# Generated by FakeRAM 2.0
VERSION 5.7 ;
BUSBITCHARS "[]" ;
PROPERTYDEFINITIONS
  MACRO width INTEGER ;
  MACRO depth INTEGER ;
  MACRO banks INTEGER ;
END PROPERTYDEFINITIONS
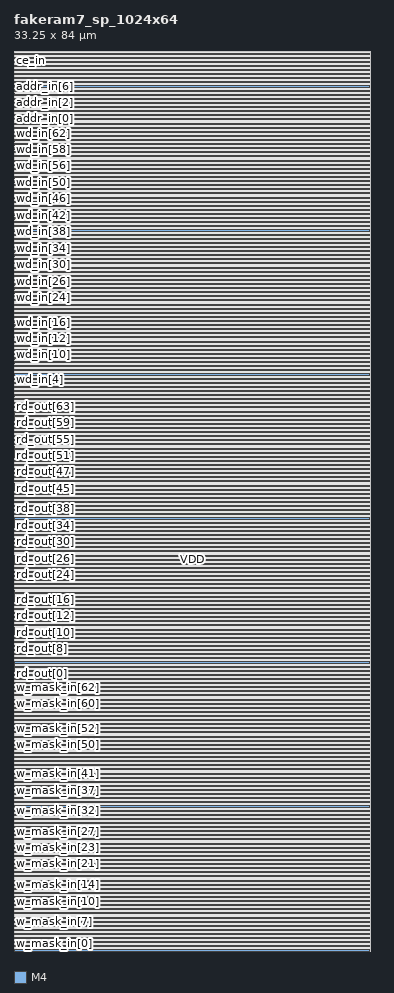
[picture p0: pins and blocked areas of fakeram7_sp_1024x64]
MACRO fakeram7_sp_1024x64
  PROPERTY width 64 ;
  PROPERTY depth 1024 ;
  PROPERTY banks 4 ;
  FOREIGN fakeram7_sp_1024x64 0 0 ;
  SYMMETRY X Y ;
  SIZE 33.250 BY 84.000 ;
  CLASS BLOCK ;
  PIN w_mask_in[0]
    DIRECTION INPUT ;
    USE SIGNAL ;
    SHAPE ABUTMENT ;
    PORT
      LAYER M4 ;
      RECT 0.000 0.048 0.024 0.072 ;
    END
  END w_mask_in[0]
  PIN w_mask_in[1]
    DIRECTION INPUT ;
    USE SIGNAL ;
    SHAPE ABUTMENT ;
    PORT
      LAYER M4 ;
      RECT 0.000 0.432 0.024 0.456 ;
    END
  END w_mask_in[1]
  PIN w_mask_in[2]
    DIRECTION INPUT ;
    USE SIGNAL ;
    SHAPE ABUTMENT ;
    PORT
      LAYER M4 ;
      RECT 0.000 0.816 0.024 0.840 ;
    END
  END w_mask_in[2]
  PIN w_mask_in[3]
    DIRECTION INPUT ;
    USE SIGNAL ;
    SHAPE ABUTMENT ;
    PORT
      LAYER M4 ;
      RECT 0.000 1.200 0.024 1.224 ;
    END
  END w_mask_in[3]
  PIN w_mask_in[4]
    DIRECTION INPUT ;
    USE SIGNAL ;
    SHAPE ABUTMENT ;
    PORT
      LAYER M4 ;
      RECT 0.000 1.584 0.024 1.608 ;
    END
  END w_mask_in[4]
  PIN w_mask_in[5]
    DIRECTION INPUT ;
    USE SIGNAL ;
    SHAPE ABUTMENT ;
    PORT
      LAYER M4 ;
      RECT 0.000 1.968 0.024 1.992 ;
    END
  END w_mask_in[5]
  PIN w_mask_in[6]
    DIRECTION INPUT ;
    USE SIGNAL ;
    SHAPE ABUTMENT ;
    PORT
      LAYER M4 ;
      RECT 0.000 2.352 0.024 2.376 ;
    END
  END w_mask_in[6]
  PIN w_mask_in[7]
    DIRECTION INPUT ;
    USE SIGNAL ;
    SHAPE ABUTMENT ;
    PORT
      LAYER M4 ;
      RECT 0.000 2.736 0.024 2.760 ;
    END
  END w_mask_in[7]
  PIN w_mask_in[8]
    DIRECTION INPUT ;
    USE SIGNAL ;
    SHAPE ABUTMENT ;
    PORT
      LAYER M4 ;
      RECT 0.000 3.120 0.024 3.144 ;
    END
  END w_mask_in[8]
  PIN w_mask_in[9]
    DIRECTION INPUT ;
    USE SIGNAL ;
    SHAPE ABUTMENT ;
    PORT
      LAYER M4 ;
      RECT 0.000 3.504 0.024 3.528 ;
    END
  END w_mask_in[9]
  PIN w_mask_in[10]
    DIRECTION INPUT ;
    USE SIGNAL ;
    SHAPE ABUTMENT ;
    PORT
      LAYER M4 ;
      RECT 0.000 3.888 0.024 3.912 ;
    END
  END w_mask_in[10]
  PIN w_mask_in[11]
    DIRECTION INPUT ;
    USE SIGNAL ;
    SHAPE ABUTMENT ;
    PORT
      LAYER M4 ;
      RECT 0.000 4.272 0.024 4.296 ;
    END
  END w_mask_in[11]
  PIN w_mask_in[12]
    DIRECTION INPUT ;
    USE SIGNAL ;
    SHAPE ABUTMENT ;
    PORT
      LAYER M4 ;
      RECT 0.000 4.656 0.024 4.680 ;
    END
  END w_mask_in[12]
  PIN w_mask_in[13]
    DIRECTION INPUT ;
    USE SIGNAL ;
    SHAPE ABUTMENT ;
    PORT
      LAYER M4 ;
      RECT 0.000 5.040 0.024 5.064 ;
    END
  END w_mask_in[13]
  PIN w_mask_in[14]
    DIRECTION INPUT ;
    USE SIGNAL ;
    SHAPE ABUTMENT ;
    PORT
      LAYER M4 ;
      RECT 0.000 5.424 0.024 5.448 ;
    END
  END w_mask_in[14]
  PIN w_mask_in[15]
    DIRECTION INPUT ;
    USE SIGNAL ;
    SHAPE ABUTMENT ;
    PORT
      LAYER M4 ;
      RECT 0.000 5.808 0.024 5.832 ;
    END
  END w_mask_in[15]
  PIN w_mask_in[16]
    DIRECTION INPUT ;
    USE SIGNAL ;
    SHAPE ABUTMENT ;
    PORT
      LAYER M4 ;
      RECT 0.000 6.192 0.024 6.216 ;
    END
  END w_mask_in[16]
  PIN w_mask_in[17]
    DIRECTION INPUT ;
    USE SIGNAL ;
    SHAPE ABUTMENT ;
    PORT
      LAYER M4 ;
      RECT 0.000 6.576 0.024 6.600 ;
    END
  END w_mask_in[17]
  PIN w_mask_in[18]
    DIRECTION INPUT ;
    USE SIGNAL ;
    SHAPE ABUTMENT ;
    PORT
      LAYER M4 ;
      RECT 0.000 6.960 0.024 6.984 ;
    END
  END w_mask_in[18]
  PIN w_mask_in[19]
    DIRECTION INPUT ;
    USE SIGNAL ;
    SHAPE ABUTMENT ;
    PORT
      LAYER M4 ;
      RECT 0.000 7.344 0.024 7.368 ;
    END
  END w_mask_in[19]
  PIN w_mask_in[20]
    DIRECTION INPUT ;
    USE SIGNAL ;
    SHAPE ABUTMENT ;
    PORT
      LAYER M4 ;
      RECT 0.000 7.728 0.024 7.752 ;
    END
  END w_mask_in[20]
  PIN w_mask_in[21]
    DIRECTION INPUT ;
    USE SIGNAL ;
    SHAPE ABUTMENT ;
    PORT
      LAYER M4 ;
      RECT 0.000 8.112 0.024 8.136 ;
    END
  END w_mask_in[21]
  PIN w_mask_in[22]
    DIRECTION INPUT ;
    USE SIGNAL ;
    SHAPE ABUTMENT ;
    PORT
      LAYER M4 ;
      RECT 0.000 8.496 0.024 8.520 ;
    END
  END w_mask_in[22]
  PIN w_mask_in[23]
    DIRECTION INPUT ;
    USE SIGNAL ;
    SHAPE ABUTMENT ;
    PORT
      LAYER M4 ;
      RECT 0.000 8.880 0.024 8.904 ;
    END
  END w_mask_in[23]
  PIN w_mask_in[24]
    DIRECTION INPUT ;
    USE SIGNAL ;
    SHAPE ABUTMENT ;
    PORT
      LAYER M4 ;
      RECT 0.000 9.264 0.024 9.288 ;
    END
  END w_mask_in[24]
  PIN w_mask_in[25]
    DIRECTION INPUT ;
    USE SIGNAL ;
    SHAPE ABUTMENT ;
    PORT
      LAYER M4 ;
      RECT 0.000 9.648 0.024 9.672 ;
    END
  END w_mask_in[25]
  PIN w_mask_in[26]
    DIRECTION INPUT ;
    USE SIGNAL ;
    SHAPE ABUTMENT ;
    PORT
      LAYER M4 ;
      RECT 0.000 10.032 0.024 10.056 ;
    END
  END w_mask_in[26]
  PIN w_mask_in[27]
    DIRECTION INPUT ;
    USE SIGNAL ;
    SHAPE ABUTMENT ;
    PORT
      LAYER M4 ;
      RECT 0.000 10.416 0.024 10.440 ;
    END
  END w_mask_in[27]
  PIN w_mask_in[28]
    DIRECTION INPUT ;
    USE SIGNAL ;
    SHAPE ABUTMENT ;
    PORT
      LAYER M4 ;
      RECT 0.000 10.800 0.024 10.824 ;
    END
  END w_mask_in[28]
  PIN w_mask_in[29]
    DIRECTION INPUT ;
    USE SIGNAL ;
    SHAPE ABUTMENT ;
    PORT
      LAYER M4 ;
      RECT 0.000 11.184 0.024 11.208 ;
    END
  END w_mask_in[29]
  PIN w_mask_in[30]
    DIRECTION INPUT ;
    USE SIGNAL ;
    SHAPE ABUTMENT ;
    PORT
      LAYER M4 ;
      RECT 0.000 11.568 0.024 11.592 ;
    END
  END w_mask_in[30]
  PIN w_mask_in[31]
    DIRECTION INPUT ;
    USE SIGNAL ;
    SHAPE ABUTMENT ;
    PORT
      LAYER M4 ;
      RECT 0.000 11.952 0.024 11.976 ;
    END
  END w_mask_in[31]
  PIN w_mask_in[32]
    DIRECTION INPUT ;
    USE SIGNAL ;
    SHAPE ABUTMENT ;
    PORT
      LAYER M4 ;
      RECT 0.000 12.336 0.024 12.360 ;
    END
  END w_mask_in[32]
  PIN w_mask_in[33]
    DIRECTION INPUT ;
    USE SIGNAL ;
    SHAPE ABUTMENT ;
    PORT
      LAYER M4 ;
      RECT 0.000 12.720 0.024 12.744 ;
    END
  END w_mask_in[33]
  PIN w_mask_in[34]
    DIRECTION INPUT ;
    USE SIGNAL ;
    SHAPE ABUTMENT ;
    PORT
      LAYER M4 ;
      RECT 0.000 13.104 0.024 13.128 ;
    END
  END w_mask_in[34]
  PIN w_mask_in[35]
    DIRECTION INPUT ;
    USE SIGNAL ;
    SHAPE ABUTMENT ;
    PORT
      LAYER M4 ;
      RECT 0.000 13.488 0.024 13.512 ;
    END
  END w_mask_in[35]
  PIN w_mask_in[36]
    DIRECTION INPUT ;
    USE SIGNAL ;
    SHAPE ABUTMENT ;
    PORT
      LAYER M4 ;
      RECT 0.000 13.872 0.024 13.896 ;
    END
  END w_mask_in[36]
  PIN w_mask_in[37]
    DIRECTION INPUT ;
    USE SIGNAL ;
    SHAPE ABUTMENT ;
    PORT
      LAYER M4 ;
      RECT 0.000 14.256 0.024 14.280 ;
    END
  END w_mask_in[37]
  PIN w_mask_in[38]
    DIRECTION INPUT ;
    USE SIGNAL ;
    SHAPE ABUTMENT ;
    PORT
      LAYER M4 ;
      RECT 0.000 14.640 0.024 14.664 ;
    END
  END w_mask_in[38]
  PIN w_mask_in[39]
    DIRECTION INPUT ;
    USE SIGNAL ;
    SHAPE ABUTMENT ;
    PORT
      LAYER M4 ;
      RECT 0.000 15.024 0.024 15.048 ;
    END
  END w_mask_in[39]
  PIN w_mask_in[40]
    DIRECTION INPUT ;
    USE SIGNAL ;
    SHAPE ABUTMENT ;
    PORT
      LAYER M4 ;
      RECT 0.000 15.408 0.024 15.432 ;
    END
  END w_mask_in[40]
  PIN w_mask_in[41]
    DIRECTION INPUT ;
    USE SIGNAL ;
    SHAPE ABUTMENT ;
    PORT
      LAYER M4 ;
      RECT 0.000 15.792 0.024 15.816 ;
    END
  END w_mask_in[41]
  PIN w_mask_in[42]
    DIRECTION INPUT ;
    USE SIGNAL ;
    SHAPE ABUTMENT ;
    PORT
      LAYER M4 ;
      RECT 0.000 16.176 0.024 16.200 ;
    END
  END w_mask_in[42]
  PIN w_mask_in[43]
    DIRECTION INPUT ;
    USE SIGNAL ;
    SHAPE ABUTMENT ;
    PORT
      LAYER M4 ;
      RECT 0.000 16.560 0.024 16.584 ;
    END
  END w_mask_in[43]
  PIN w_mask_in[44]
    DIRECTION INPUT ;
    USE SIGNAL ;
    SHAPE ABUTMENT ;
    PORT
      LAYER M4 ;
      RECT 0.000 16.944 0.024 16.968 ;
    END
  END w_mask_in[44]
  PIN w_mask_in[45]
    DIRECTION INPUT ;
    USE SIGNAL ;
    SHAPE ABUTMENT ;
    PORT
      LAYER M4 ;
      RECT 0.000 17.328 0.024 17.352 ;
    END
  END w_mask_in[45]
  PIN w_mask_in[46]
    DIRECTION INPUT ;
    USE SIGNAL ;
    SHAPE ABUTMENT ;
    PORT
      LAYER M4 ;
      RECT 0.000 17.712 0.024 17.736 ;
    END
  END w_mask_in[46]
  PIN w_mask_in[47]
    DIRECTION INPUT ;
    USE SIGNAL ;
    SHAPE ABUTMENT ;
    PORT
      LAYER M4 ;
      RECT 0.000 18.096 0.024 18.120 ;
    END
  END w_mask_in[47]
  PIN w_mask_in[48]
    DIRECTION INPUT ;
    USE SIGNAL ;
    SHAPE ABUTMENT ;
    PORT
      LAYER M4 ;
      RECT 0.000 18.480 0.024 18.504 ;
    END
  END w_mask_in[48]
  PIN w_mask_in[49]
    DIRECTION INPUT ;
    USE SIGNAL ;
    SHAPE ABUTMENT ;
    PORT
      LAYER M4 ;
      RECT 0.000 18.864 0.024 18.888 ;
    END
  END w_mask_in[49]
  PIN w_mask_in[50]
    DIRECTION INPUT ;
    USE SIGNAL ;
    SHAPE ABUTMENT ;
    PORT
      LAYER M4 ;
      RECT 0.000 19.248 0.024 19.272 ;
    END
  END w_mask_in[50]
  PIN w_mask_in[51]
    DIRECTION INPUT ;
    USE SIGNAL ;
    SHAPE ABUTMENT ;
    PORT
      LAYER M4 ;
      RECT 0.000 19.632 0.024 19.656 ;
    END
  END w_mask_in[51]
  PIN w_mask_in[52]
    DIRECTION INPUT ;
    USE SIGNAL ;
    SHAPE ABUTMENT ;
    PORT
      LAYER M4 ;
      RECT 0.000 20.016 0.024 20.040 ;
    END
  END w_mask_in[52]
  PIN w_mask_in[53]
    DIRECTION INPUT ;
    USE SIGNAL ;
    SHAPE ABUTMENT ;
    PORT
      LAYER M4 ;
      RECT 0.000 20.400 0.024 20.424 ;
    END
  END w_mask_in[53]
  PIN w_mask_in[54]
    DIRECTION INPUT ;
    USE SIGNAL ;
    SHAPE ABUTMENT ;
    PORT
      LAYER M4 ;
      RECT 0.000 20.784 0.024 20.808 ;
    END
  END w_mask_in[54]
  PIN w_mask_in[55]
    DIRECTION INPUT ;
    USE SIGNAL ;
    SHAPE ABUTMENT ;
    PORT
      LAYER M4 ;
      RECT 0.000 21.168 0.024 21.192 ;
    END
  END w_mask_in[55]
  PIN w_mask_in[56]
    DIRECTION INPUT ;
    USE SIGNAL ;
    SHAPE ABUTMENT ;
    PORT
      LAYER M4 ;
      RECT 0.000 21.552 0.024 21.576 ;
    END
  END w_mask_in[56]
  PIN w_mask_in[57]
    DIRECTION INPUT ;
    USE SIGNAL ;
    SHAPE ABUTMENT ;
    PORT
      LAYER M4 ;
      RECT 0.000 21.936 0.024 21.960 ;
    END
  END w_mask_in[57]
  PIN w_mask_in[58]
    DIRECTION INPUT ;
    USE SIGNAL ;
    SHAPE ABUTMENT ;
    PORT
      LAYER M4 ;
      RECT 0.000 22.320 0.024 22.344 ;
    END
  END w_mask_in[58]
  PIN w_mask_in[59]
    DIRECTION INPUT ;
    USE SIGNAL ;
    SHAPE ABUTMENT ;
    PORT
      LAYER M4 ;
      RECT 0.000 22.704 0.024 22.728 ;
    END
  END w_mask_in[59]
  PIN w_mask_in[60]
    DIRECTION INPUT ;
    USE SIGNAL ;
    SHAPE ABUTMENT ;
    PORT
      LAYER M4 ;
      RECT 0.000 23.088 0.024 23.112 ;
    END
  END w_mask_in[60]
  PIN w_mask_in[61]
    DIRECTION INPUT ;
    USE SIGNAL ;
    SHAPE ABUTMENT ;
    PORT
      LAYER M4 ;
      RECT 0.000 23.472 0.024 23.496 ;
    END
  END w_mask_in[61]
  PIN w_mask_in[62]
    DIRECTION INPUT ;
    USE SIGNAL ;
    SHAPE ABUTMENT ;
    PORT
      LAYER M4 ;
      RECT 0.000 23.856 0.024 23.880 ;
    END
  END w_mask_in[62]
  PIN w_mask_in[63]
    DIRECTION INPUT ;
    USE SIGNAL ;
    SHAPE ABUTMENT ;
    PORT
      LAYER M4 ;
      RECT 0.000 24.240 0.024 24.264 ;
    END
  END w_mask_in[63]
  PIN rd_out[0]
    DIRECTION OUTPUT ;
    USE SIGNAL ;
    SHAPE ABUTMENT ;
    PORT
      LAYER M4 ;
      RECT 0.000 25.920 0.024 25.944 ;
    END
  END rd_out[0]
  PIN rd_out[1]
    DIRECTION OUTPUT ;
    USE SIGNAL ;
    SHAPE ABUTMENT ;
    PORT
      LAYER M4 ;
      RECT 0.000 26.304 0.024 26.328 ;
    END
  END rd_out[1]
  PIN rd_out[2]
    DIRECTION OUTPUT ;
    USE SIGNAL ;
    SHAPE ABUTMENT ;
    PORT
      LAYER M4 ;
      RECT 0.000 26.688 0.024 26.712 ;
    END
  END rd_out[2]
  PIN rd_out[3]
    DIRECTION OUTPUT ;
    USE SIGNAL ;
    SHAPE ABUTMENT ;
    PORT
      LAYER M4 ;
      RECT 0.000 27.072 0.024 27.096 ;
    END
  END rd_out[3]
  PIN rd_out[4]
    DIRECTION OUTPUT ;
    USE SIGNAL ;
    SHAPE ABUTMENT ;
    PORT
      LAYER M4 ;
      RECT 0.000 27.456 0.024 27.480 ;
    END
  END rd_out[4]
  PIN rd_out[5]
    DIRECTION OUTPUT ;
    USE SIGNAL ;
    SHAPE ABUTMENT ;
    PORT
      LAYER M4 ;
      RECT 0.000 27.840 0.024 27.864 ;
    END
  END rd_out[5]
  PIN rd_out[6]
    DIRECTION OUTPUT ;
    USE SIGNAL ;
    SHAPE ABUTMENT ;
    PORT
      LAYER M4 ;
      RECT 0.000 28.224 0.024 28.248 ;
    END
  END rd_out[6]
  PIN rd_out[7]
    DIRECTION OUTPUT ;
    USE SIGNAL ;
    SHAPE ABUTMENT ;
    PORT
      LAYER M4 ;
      RECT 0.000 28.608 0.024 28.632 ;
    END
  END rd_out[7]
  PIN rd_out[8]
    DIRECTION OUTPUT ;
    USE SIGNAL ;
    SHAPE ABUTMENT ;
    PORT
      LAYER M4 ;
      RECT 0.000 28.992 0.024 29.016 ;
    END
  END rd_out[8]
  PIN rd_out[9]
    DIRECTION OUTPUT ;
    USE SIGNAL ;
    SHAPE ABUTMENT ;
    PORT
      LAYER M4 ;
      RECT 0.000 29.376 0.024 29.400 ;
    END
  END rd_out[9]
  PIN rd_out[10]
    DIRECTION OUTPUT ;
    USE SIGNAL ;
    SHAPE ABUTMENT ;
    PORT
      LAYER M4 ;
      RECT 0.000 29.760 0.024 29.784 ;
    END
  END rd_out[10]
  PIN rd_out[11]
    DIRECTION OUTPUT ;
    USE SIGNAL ;
    SHAPE ABUTMENT ;
    PORT
      LAYER M4 ;
      RECT 0.000 30.144 0.024 30.168 ;
    END
  END rd_out[11]
  PIN rd_out[12]
    DIRECTION OUTPUT ;
    USE SIGNAL ;
    SHAPE ABUTMENT ;
    PORT
      LAYER M4 ;
      RECT 0.000 30.528 0.024 30.552 ;
    END
  END rd_out[12]
  PIN rd_out[13]
    DIRECTION OUTPUT ;
    USE SIGNAL ;
    SHAPE ABUTMENT ;
    PORT
      LAYER M4 ;
      RECT 0.000 30.912 0.024 30.936 ;
    END
  END rd_out[13]
  PIN rd_out[14]
    DIRECTION OUTPUT ;
    USE SIGNAL ;
    SHAPE ABUTMENT ;
    PORT
      LAYER M4 ;
      RECT 0.000 31.296 0.024 31.320 ;
    END
  END rd_out[14]
  PIN rd_out[15]
    DIRECTION OUTPUT ;
    USE SIGNAL ;
    SHAPE ABUTMENT ;
    PORT
      LAYER M4 ;
      RECT 0.000 31.680 0.024 31.704 ;
    END
  END rd_out[15]
  PIN rd_out[16]
    DIRECTION OUTPUT ;
    USE SIGNAL ;
    SHAPE ABUTMENT ;
    PORT
      LAYER M4 ;
      RECT 0.000 32.064 0.024 32.088 ;
    END
  END rd_out[16]
  PIN rd_out[17]
    DIRECTION OUTPUT ;
    USE SIGNAL ;
    SHAPE ABUTMENT ;
    PORT
      LAYER M4 ;
      RECT 0.000 32.448 0.024 32.472 ;
    END
  END rd_out[17]
  PIN rd_out[18]
    DIRECTION OUTPUT ;
    USE SIGNAL ;
    SHAPE ABUTMENT ;
    PORT
      LAYER M4 ;
      RECT 0.000 32.832 0.024 32.856 ;
    END
  END rd_out[18]
  PIN rd_out[19]
    DIRECTION OUTPUT ;
    USE SIGNAL ;
    SHAPE ABUTMENT ;
    PORT
      LAYER M4 ;
      RECT 0.000 33.216 0.024 33.240 ;
    END
  END rd_out[19]
  PIN rd_out[20]
    DIRECTION OUTPUT ;
    USE SIGNAL ;
    SHAPE ABUTMENT ;
    PORT
      LAYER M4 ;
      RECT 0.000 33.600 0.024 33.624 ;
    END
  END rd_out[20]
  PIN rd_out[21]
    DIRECTION OUTPUT ;
    USE SIGNAL ;
    SHAPE ABUTMENT ;
    PORT
      LAYER M4 ;
      RECT 0.000 33.984 0.024 34.008 ;
    END
  END rd_out[21]
  PIN rd_out[22]
    DIRECTION OUTPUT ;
    USE SIGNAL ;
    SHAPE ABUTMENT ;
    PORT
      LAYER M4 ;
      RECT 0.000 34.368 0.024 34.392 ;
    END
  END rd_out[22]
  PIN rd_out[23]
    DIRECTION OUTPUT ;
    USE SIGNAL ;
    SHAPE ABUTMENT ;
    PORT
      LAYER M4 ;
      RECT 0.000 34.752 0.024 34.776 ;
    END
  END rd_out[23]
  PIN rd_out[24]
    DIRECTION OUTPUT ;
    USE SIGNAL ;
    SHAPE ABUTMENT ;
    PORT
      LAYER M4 ;
      RECT 0.000 35.136 0.024 35.160 ;
    END
  END rd_out[24]
  PIN rd_out[25]
    DIRECTION OUTPUT ;
    USE SIGNAL ;
    SHAPE ABUTMENT ;
    PORT
      LAYER M4 ;
      RECT 0.000 35.520 0.024 35.544 ;
    END
  END rd_out[25]
  PIN rd_out[26]
    DIRECTION OUTPUT ;
    USE SIGNAL ;
    SHAPE ABUTMENT ;
    PORT
      LAYER M4 ;
      RECT 0.000 35.904 0.024 35.928 ;
    END
  END rd_out[26]
  PIN rd_out[27]
    DIRECTION OUTPUT ;
    USE SIGNAL ;
    SHAPE ABUTMENT ;
    PORT
      LAYER M4 ;
      RECT 0.000 36.288 0.024 36.312 ;
    END
  END rd_out[27]
  PIN rd_out[28]
    DIRECTION OUTPUT ;
    USE SIGNAL ;
    SHAPE ABUTMENT ;
    PORT
      LAYER M4 ;
      RECT 0.000 36.672 0.024 36.696 ;
    END
  END rd_out[28]
  PIN rd_out[29]
    DIRECTION OUTPUT ;
    USE SIGNAL ;
    SHAPE ABUTMENT ;
    PORT
      LAYER M4 ;
      RECT 0.000 37.056 0.024 37.080 ;
    END
  END rd_out[29]
  PIN rd_out[30]
    DIRECTION OUTPUT ;
    USE SIGNAL ;
    SHAPE ABUTMENT ;
    PORT
      LAYER M4 ;
      RECT 0.000 37.440 0.024 37.464 ;
    END
  END rd_out[30]
  PIN rd_out[31]
    DIRECTION OUTPUT ;
    USE SIGNAL ;
    SHAPE ABUTMENT ;
    PORT
      LAYER M4 ;
      RECT 0.000 37.824 0.024 37.848 ;
    END
  END rd_out[31]
  PIN rd_out[32]
    DIRECTION OUTPUT ;
    USE SIGNAL ;
    SHAPE ABUTMENT ;
    PORT
      LAYER M4 ;
      RECT 0.000 38.208 0.024 38.232 ;
    END
  END rd_out[32]
  PIN rd_out[33]
    DIRECTION OUTPUT ;
    USE SIGNAL ;
    SHAPE ABUTMENT ;
    PORT
      LAYER M4 ;
      RECT 0.000 38.592 0.024 38.616 ;
    END
  END rd_out[33]
  PIN rd_out[34]
    DIRECTION OUTPUT ;
    USE SIGNAL ;
    SHAPE ABUTMENT ;
    PORT
      LAYER M4 ;
      RECT 0.000 38.976 0.024 39.000 ;
    END
  END rd_out[34]
  PIN rd_out[35]
    DIRECTION OUTPUT ;
    USE SIGNAL ;
    SHAPE ABUTMENT ;
    PORT
      LAYER M4 ;
      RECT 0.000 39.360 0.024 39.384 ;
    END
  END rd_out[35]
  PIN rd_out[36]
    DIRECTION OUTPUT ;
    USE SIGNAL ;
    SHAPE ABUTMENT ;
    PORT
      LAYER M4 ;
      RECT 0.000 39.744 0.024 39.768 ;
    END
  END rd_out[36]
  PIN rd_out[37]
    DIRECTION OUTPUT ;
    USE SIGNAL ;
    SHAPE ABUTMENT ;
    PORT
      LAYER M4 ;
      RECT 0.000 40.128 0.024 40.152 ;
    END
  END rd_out[37]
  PIN rd_out[38]
    DIRECTION OUTPUT ;
    USE SIGNAL ;
    SHAPE ABUTMENT ;
    PORT
      LAYER M4 ;
      RECT 0.000 40.512 0.024 40.536 ;
    END
  END rd_out[38]
  PIN rd_out[39]
    DIRECTION OUTPUT ;
    USE SIGNAL ;
    SHAPE ABUTMENT ;
    PORT
      LAYER M4 ;
      RECT 0.000 40.896 0.024 40.920 ;
    END
  END rd_out[39]
  PIN rd_out[40]
    DIRECTION OUTPUT ;
    USE SIGNAL ;
    SHAPE ABUTMENT ;
    PORT
      LAYER M4 ;
      RECT 0.000 41.280 0.024 41.304 ;
    END
  END rd_out[40]
  PIN rd_out[41]
    DIRECTION OUTPUT ;
    USE SIGNAL ;
    SHAPE ABUTMENT ;
    PORT
      LAYER M4 ;
      RECT 0.000 41.664 0.024 41.688 ;
    END
  END rd_out[41]
  PIN rd_out[42]
    DIRECTION OUTPUT ;
    USE SIGNAL ;
    SHAPE ABUTMENT ;
    PORT
      LAYER M4 ;
      RECT 0.000 42.048 0.024 42.072 ;
    END
  END rd_out[42]
  PIN rd_out[43]
    DIRECTION OUTPUT ;
    USE SIGNAL ;
    SHAPE ABUTMENT ;
    PORT
      LAYER M4 ;
      RECT 0.000 42.432 0.024 42.456 ;
    END
  END rd_out[43]
  PIN rd_out[44]
    DIRECTION OUTPUT ;
    USE SIGNAL ;
    SHAPE ABUTMENT ;
    PORT
      LAYER M4 ;
      RECT 0.000 42.816 0.024 42.840 ;
    END
  END rd_out[44]
  PIN rd_out[45]
    DIRECTION OUTPUT ;
    USE SIGNAL ;
    SHAPE ABUTMENT ;
    PORT
      LAYER M4 ;
      RECT 0.000 43.200 0.024 43.224 ;
    END
  END rd_out[45]
  PIN rd_out[46]
    DIRECTION OUTPUT ;
    USE SIGNAL ;
    SHAPE ABUTMENT ;
    PORT
      LAYER M4 ;
      RECT 0.000 43.584 0.024 43.608 ;
    END
  END rd_out[46]
  PIN rd_out[47]
    DIRECTION OUTPUT ;
    USE SIGNAL ;
    SHAPE ABUTMENT ;
    PORT
      LAYER M4 ;
      RECT 0.000 43.968 0.024 43.992 ;
    END
  END rd_out[47]
  PIN rd_out[48]
    DIRECTION OUTPUT ;
    USE SIGNAL ;
    SHAPE ABUTMENT ;
    PORT
      LAYER M4 ;
      RECT 0.000 44.352 0.024 44.376 ;
    END
  END rd_out[48]
  PIN rd_out[49]
    DIRECTION OUTPUT ;
    USE SIGNAL ;
    SHAPE ABUTMENT ;
    PORT
      LAYER M4 ;
      RECT 0.000 44.736 0.024 44.760 ;
    END
  END rd_out[49]
  PIN rd_out[50]
    DIRECTION OUTPUT ;
    USE SIGNAL ;
    SHAPE ABUTMENT ;
    PORT
      LAYER M4 ;
      RECT 0.000 45.120 0.024 45.144 ;
    END
  END rd_out[50]
  PIN rd_out[51]
    DIRECTION OUTPUT ;
    USE SIGNAL ;
    SHAPE ABUTMENT ;
    PORT
      LAYER M4 ;
      RECT 0.000 45.504 0.024 45.528 ;
    END
  END rd_out[51]
  PIN rd_out[52]
    DIRECTION OUTPUT ;
    USE SIGNAL ;
    SHAPE ABUTMENT ;
    PORT
      LAYER M4 ;
      RECT 0.000 45.888 0.024 45.912 ;
    END
  END rd_out[52]
  PIN rd_out[53]
    DIRECTION OUTPUT ;
    USE SIGNAL ;
    SHAPE ABUTMENT ;
    PORT
      LAYER M4 ;
      RECT 0.000 46.272 0.024 46.296 ;
    END
  END rd_out[53]
  PIN rd_out[54]
    DIRECTION OUTPUT ;
    USE SIGNAL ;
    SHAPE ABUTMENT ;
    PORT
      LAYER M4 ;
      RECT 0.000 46.656 0.024 46.680 ;
    END
  END rd_out[54]
  PIN rd_out[55]
    DIRECTION OUTPUT ;
    USE SIGNAL ;
    SHAPE ABUTMENT ;
    PORT
      LAYER M4 ;
      RECT 0.000 47.040 0.024 47.064 ;
    END
  END rd_out[55]
  PIN rd_out[56]
    DIRECTION OUTPUT ;
    USE SIGNAL ;
    SHAPE ABUTMENT ;
    PORT
      LAYER M4 ;
      RECT 0.000 47.424 0.024 47.448 ;
    END
  END rd_out[56]
  PIN rd_out[57]
    DIRECTION OUTPUT ;
    USE SIGNAL ;
    SHAPE ABUTMENT ;
    PORT
      LAYER M4 ;
      RECT 0.000 47.808 0.024 47.832 ;
    END
  END rd_out[57]
  PIN rd_out[58]
    DIRECTION OUTPUT ;
    USE SIGNAL ;
    SHAPE ABUTMENT ;
    PORT
      LAYER M4 ;
      RECT 0.000 48.192 0.024 48.216 ;
    END
  END rd_out[58]
  PIN rd_out[59]
    DIRECTION OUTPUT ;
    USE SIGNAL ;
    SHAPE ABUTMENT ;
    PORT
      LAYER M4 ;
      RECT 0.000 48.576 0.024 48.600 ;
    END
  END rd_out[59]
  PIN rd_out[60]
    DIRECTION OUTPUT ;
    USE SIGNAL ;
    SHAPE ABUTMENT ;
    PORT
      LAYER M4 ;
      RECT 0.000 48.960 0.024 48.984 ;
    END
  END rd_out[60]
  PIN rd_out[61]
    DIRECTION OUTPUT ;
    USE SIGNAL ;
    SHAPE ABUTMENT ;
    PORT
      LAYER M4 ;
      RECT 0.000 49.344 0.024 49.368 ;
    END
  END rd_out[61]
  PIN rd_out[62]
    DIRECTION OUTPUT ;
    USE SIGNAL ;
    SHAPE ABUTMENT ;
    PORT
      LAYER M4 ;
      RECT 0.000 49.728 0.024 49.752 ;
    END
  END rd_out[62]
  PIN rd_out[63]
    DIRECTION OUTPUT ;
    USE SIGNAL ;
    SHAPE ABUTMENT ;
    PORT
      LAYER M4 ;
      RECT 0.000 50.112 0.024 50.136 ;
    END
  END rd_out[63]
  PIN wd_in[0]
    DIRECTION INPUT ;
    USE SIGNAL ;
    SHAPE ABUTMENT ;
    PORT
      LAYER M4 ;
      RECT 0.000 51.792 0.024 51.816 ;
    END
  END wd_in[0]
  PIN wd_in[1]
    DIRECTION INPUT ;
    USE SIGNAL ;
    SHAPE ABUTMENT ;
    PORT
      LAYER M4 ;
      RECT 0.000 52.176 0.024 52.200 ;
    END
  END wd_in[1]
  PIN wd_in[2]
    DIRECTION INPUT ;
    USE SIGNAL ;
    SHAPE ABUTMENT ;
    PORT
      LAYER M4 ;
      RECT 0.000 52.560 0.024 52.584 ;
    END
  END wd_in[2]
  PIN wd_in[3]
    DIRECTION INPUT ;
    USE SIGNAL ;
    SHAPE ABUTMENT ;
    PORT
      LAYER M4 ;
      RECT 0.000 52.944 0.024 52.968 ;
    END
  END wd_in[3]
  PIN wd_in[4]
    DIRECTION INPUT ;
    USE SIGNAL ;
    SHAPE ABUTMENT ;
    PORT
      LAYER M4 ;
      RECT 0.000 53.328 0.024 53.352 ;
    END
  END wd_in[4]
  PIN wd_in[5]
    DIRECTION INPUT ;
    USE SIGNAL ;
    SHAPE ABUTMENT ;
    PORT
      LAYER M4 ;
      RECT 0.000 53.712 0.024 53.736 ;
    END
  END wd_in[5]
  PIN wd_in[6]
    DIRECTION INPUT ;
    USE SIGNAL ;
    SHAPE ABUTMENT ;
    PORT
      LAYER M4 ;
      RECT 0.000 54.096 0.024 54.120 ;
    END
  END wd_in[6]
  PIN wd_in[7]
    DIRECTION INPUT ;
    USE SIGNAL ;
    SHAPE ABUTMENT ;
    PORT
      LAYER M4 ;
      RECT 0.000 54.480 0.024 54.504 ;
    END
  END wd_in[7]
  PIN wd_in[8]
    DIRECTION INPUT ;
    USE SIGNAL ;
    SHAPE ABUTMENT ;
    PORT
      LAYER M4 ;
      RECT 0.000 54.864 0.024 54.888 ;
    END
  END wd_in[8]
  PIN wd_in[9]
    DIRECTION INPUT ;
    USE SIGNAL ;
    SHAPE ABUTMENT ;
    PORT
      LAYER M4 ;
      RECT 0.000 55.248 0.024 55.272 ;
    END
  END wd_in[9]
  PIN wd_in[10]
    DIRECTION INPUT ;
    USE SIGNAL ;
    SHAPE ABUTMENT ;
    PORT
      LAYER M4 ;
      RECT 0.000 55.632 0.024 55.656 ;
    END
  END wd_in[10]
  PIN wd_in[11]
    DIRECTION INPUT ;
    USE SIGNAL ;
    SHAPE ABUTMENT ;
    PORT
      LAYER M4 ;
      RECT 0.000 56.016 0.024 56.040 ;
    END
  END wd_in[11]
  PIN wd_in[12]
    DIRECTION INPUT ;
    USE SIGNAL ;
    SHAPE ABUTMENT ;
    PORT
      LAYER M4 ;
      RECT 0.000 56.400 0.024 56.424 ;
    END
  END wd_in[12]
  PIN wd_in[13]
    DIRECTION INPUT ;
    USE SIGNAL ;
    SHAPE ABUTMENT ;
    PORT
      LAYER M4 ;
      RECT 0.000 56.784 0.024 56.808 ;
    END
  END wd_in[13]
  PIN wd_in[14]
    DIRECTION INPUT ;
    USE SIGNAL ;
    SHAPE ABUTMENT ;
    PORT
      LAYER M4 ;
      RECT 0.000 57.168 0.024 57.192 ;
    END
  END wd_in[14]
  PIN wd_in[15]
    DIRECTION INPUT ;
    USE SIGNAL ;
    SHAPE ABUTMENT ;
    PORT
      LAYER M4 ;
      RECT 0.000 57.552 0.024 57.576 ;
    END
  END wd_in[15]
  PIN wd_in[16]
    DIRECTION INPUT ;
    USE SIGNAL ;
    SHAPE ABUTMENT ;
    PORT
      LAYER M4 ;
      RECT 0.000 57.936 0.024 57.960 ;
    END
  END wd_in[16]
  PIN wd_in[17]
    DIRECTION INPUT ;
    USE SIGNAL ;
    SHAPE ABUTMENT ;
    PORT
      LAYER M4 ;
      RECT 0.000 58.320 0.024 58.344 ;
    END
  END wd_in[17]
  PIN wd_in[18]
    DIRECTION INPUT ;
    USE SIGNAL ;
    SHAPE ABUTMENT ;
    PORT
      LAYER M4 ;
      RECT 0.000 58.704 0.024 58.728 ;
    END
  END wd_in[18]
  PIN wd_in[19]
    DIRECTION INPUT ;
    USE SIGNAL ;
    SHAPE ABUTMENT ;
    PORT
      LAYER M4 ;
      RECT 0.000 59.088 0.024 59.112 ;
    END
  END wd_in[19]
  PIN wd_in[20]
    DIRECTION INPUT ;
    USE SIGNAL ;
    SHAPE ABUTMENT ;
    PORT
      LAYER M4 ;
      RECT 0.000 59.472 0.024 59.496 ;
    END
  END wd_in[20]
  PIN wd_in[21]
    DIRECTION INPUT ;
    USE SIGNAL ;
    SHAPE ABUTMENT ;
    PORT
      LAYER M4 ;
      RECT 0.000 59.856 0.024 59.880 ;
    END
  END wd_in[21]
  PIN wd_in[22]
    DIRECTION INPUT ;
    USE SIGNAL ;
    SHAPE ABUTMENT ;
    PORT
      LAYER M4 ;
      RECT 0.000 60.240 0.024 60.264 ;
    END
  END wd_in[22]
  PIN wd_in[23]
    DIRECTION INPUT ;
    USE SIGNAL ;
    SHAPE ABUTMENT ;
    PORT
      LAYER M4 ;
      RECT 0.000 60.624 0.024 60.648 ;
    END
  END wd_in[23]
  PIN wd_in[24]
    DIRECTION INPUT ;
    USE SIGNAL ;
    SHAPE ABUTMENT ;
    PORT
      LAYER M4 ;
      RECT 0.000 61.008 0.024 61.032 ;
    END
  END wd_in[24]
  PIN wd_in[25]
    DIRECTION INPUT ;
    USE SIGNAL ;
    SHAPE ABUTMENT ;
    PORT
      LAYER M4 ;
      RECT 0.000 61.392 0.024 61.416 ;
    END
  END wd_in[25]
  PIN wd_in[26]
    DIRECTION INPUT ;
    USE SIGNAL ;
    SHAPE ABUTMENT ;
    PORT
      LAYER M4 ;
      RECT 0.000 61.776 0.024 61.800 ;
    END
  END wd_in[26]
  PIN wd_in[27]
    DIRECTION INPUT ;
    USE SIGNAL ;
    SHAPE ABUTMENT ;
    PORT
      LAYER M4 ;
      RECT 0.000 62.160 0.024 62.184 ;
    END
  END wd_in[27]
  PIN wd_in[28]
    DIRECTION INPUT ;
    USE SIGNAL ;
    SHAPE ABUTMENT ;
    PORT
      LAYER M4 ;
      RECT 0.000 62.544 0.024 62.568 ;
    END
  END wd_in[28]
  PIN wd_in[29]
    DIRECTION INPUT ;
    USE SIGNAL ;
    SHAPE ABUTMENT ;
    PORT
      LAYER M4 ;
      RECT 0.000 62.928 0.024 62.952 ;
    END
  END wd_in[29]
  PIN wd_in[30]
    DIRECTION INPUT ;
    USE SIGNAL ;
    SHAPE ABUTMENT ;
    PORT
      LAYER M4 ;
      RECT 0.000 63.312 0.024 63.336 ;
    END
  END wd_in[30]
  PIN wd_in[31]
    DIRECTION INPUT ;
    USE SIGNAL ;
    SHAPE ABUTMENT ;
    PORT
      LAYER M4 ;
      RECT 0.000 63.696 0.024 63.720 ;
    END
  END wd_in[31]
  PIN wd_in[32]
    DIRECTION INPUT ;
    USE SIGNAL ;
    SHAPE ABUTMENT ;
    PORT
      LAYER M4 ;
      RECT 0.000 64.080 0.024 64.104 ;
    END
  END wd_in[32]
  PIN wd_in[33]
    DIRECTION INPUT ;
    USE SIGNAL ;
    SHAPE ABUTMENT ;
    PORT
      LAYER M4 ;
      RECT 0.000 64.464 0.024 64.488 ;
    END
  END wd_in[33]
  PIN wd_in[34]
    DIRECTION INPUT ;
    USE SIGNAL ;
    SHAPE ABUTMENT ;
    PORT
      LAYER M4 ;
      RECT 0.000 64.848 0.024 64.872 ;
    END
  END wd_in[34]
  PIN wd_in[35]
    DIRECTION INPUT ;
    USE SIGNAL ;
    SHAPE ABUTMENT ;
    PORT
      LAYER M4 ;
      RECT 0.000 65.232 0.024 65.256 ;
    END
  END wd_in[35]
  PIN wd_in[36]
    DIRECTION INPUT ;
    USE SIGNAL ;
    SHAPE ABUTMENT ;
    PORT
      LAYER M4 ;
      RECT 0.000 65.616 0.024 65.640 ;
    END
  END wd_in[36]
  PIN wd_in[37]
    DIRECTION INPUT ;
    USE SIGNAL ;
    SHAPE ABUTMENT ;
    PORT
      LAYER M4 ;
      RECT 0.000 66.000 0.024 66.024 ;
    END
  END wd_in[37]
  PIN wd_in[38]
    DIRECTION INPUT ;
    USE SIGNAL ;
    SHAPE ABUTMENT ;
    PORT
      LAYER M4 ;
      RECT 0.000 66.384 0.024 66.408 ;
    END
  END wd_in[38]
  PIN wd_in[39]
    DIRECTION INPUT ;
    USE SIGNAL ;
    SHAPE ABUTMENT ;
    PORT
      LAYER M4 ;
      RECT 0.000 66.768 0.024 66.792 ;
    END
  END wd_in[39]
  PIN wd_in[40]
    DIRECTION INPUT ;
    USE SIGNAL ;
    SHAPE ABUTMENT ;
    PORT
      LAYER M4 ;
      RECT 0.000 67.152 0.024 67.176 ;
    END
  END wd_in[40]
  PIN wd_in[41]
    DIRECTION INPUT ;
    USE SIGNAL ;
    SHAPE ABUTMENT ;
    PORT
      LAYER M4 ;
      RECT 0.000 67.536 0.024 67.560 ;
    END
  END wd_in[41]
  PIN wd_in[42]
    DIRECTION INPUT ;
    USE SIGNAL ;
    SHAPE ABUTMENT ;
    PORT
      LAYER M4 ;
      RECT 0.000 67.920 0.024 67.944 ;
    END
  END wd_in[42]
  PIN wd_in[43]
    DIRECTION INPUT ;
    USE SIGNAL ;
    SHAPE ABUTMENT ;
    PORT
      LAYER M4 ;
      RECT 0.000 68.304 0.024 68.328 ;
    END
  END wd_in[43]
  PIN wd_in[44]
    DIRECTION INPUT ;
    USE SIGNAL ;
    SHAPE ABUTMENT ;
    PORT
      LAYER M4 ;
      RECT 0.000 68.688 0.024 68.712 ;
    END
  END wd_in[44]
  PIN wd_in[45]
    DIRECTION INPUT ;
    USE SIGNAL ;
    SHAPE ABUTMENT ;
    PORT
      LAYER M4 ;
      RECT 0.000 69.072 0.024 69.096 ;
    END
  END wd_in[45]
  PIN wd_in[46]
    DIRECTION INPUT ;
    USE SIGNAL ;
    SHAPE ABUTMENT ;
    PORT
      LAYER M4 ;
      RECT 0.000 69.456 0.024 69.480 ;
    END
  END wd_in[46]
  PIN wd_in[47]
    DIRECTION INPUT ;
    USE SIGNAL ;
    SHAPE ABUTMENT ;
    PORT
      LAYER M4 ;
      RECT 0.000 69.840 0.024 69.864 ;
    END
  END wd_in[47]
  PIN wd_in[48]
    DIRECTION INPUT ;
    USE SIGNAL ;
    SHAPE ABUTMENT ;
    PORT
      LAYER M4 ;
      RECT 0.000 70.224 0.024 70.248 ;
    END
  END wd_in[48]
  PIN wd_in[49]
    DIRECTION INPUT ;
    USE SIGNAL ;
    SHAPE ABUTMENT ;
    PORT
      LAYER M4 ;
      RECT 0.000 70.608 0.024 70.632 ;
    END
  END wd_in[49]
  PIN wd_in[50]
    DIRECTION INPUT ;
    USE SIGNAL ;
    SHAPE ABUTMENT ;
    PORT
      LAYER M4 ;
      RECT 0.000 70.992 0.024 71.016 ;
    END
  END wd_in[50]
  PIN wd_in[51]
    DIRECTION INPUT ;
    USE SIGNAL ;
    SHAPE ABUTMENT ;
    PORT
      LAYER M4 ;
      RECT 0.000 71.376 0.024 71.400 ;
    END
  END wd_in[51]
  PIN wd_in[52]
    DIRECTION INPUT ;
    USE SIGNAL ;
    SHAPE ABUTMENT ;
    PORT
      LAYER M4 ;
      RECT 0.000 71.760 0.024 71.784 ;
    END
  END wd_in[52]
  PIN wd_in[53]
    DIRECTION INPUT ;
    USE SIGNAL ;
    SHAPE ABUTMENT ;
    PORT
      LAYER M4 ;
      RECT 0.000 72.144 0.024 72.168 ;
    END
  END wd_in[53]
  PIN wd_in[54]
    DIRECTION INPUT ;
    USE SIGNAL ;
    SHAPE ABUTMENT ;
    PORT
      LAYER M4 ;
      RECT 0.000 72.528 0.024 72.552 ;
    END
  END wd_in[54]
  PIN wd_in[55]
    DIRECTION INPUT ;
    USE SIGNAL ;
    SHAPE ABUTMENT ;
    PORT
      LAYER M4 ;
      RECT 0.000 72.912 0.024 72.936 ;
    END
  END wd_in[55]
  PIN wd_in[56]
    DIRECTION INPUT ;
    USE SIGNAL ;
    SHAPE ABUTMENT ;
    PORT
      LAYER M4 ;
      RECT 0.000 73.296 0.024 73.320 ;
    END
  END wd_in[56]
  PIN wd_in[57]
    DIRECTION INPUT ;
    USE SIGNAL ;
    SHAPE ABUTMENT ;
    PORT
      LAYER M4 ;
      RECT 0.000 73.680 0.024 73.704 ;
    END
  END wd_in[57]
  PIN wd_in[58]
    DIRECTION INPUT ;
    USE SIGNAL ;
    SHAPE ABUTMENT ;
    PORT
      LAYER M4 ;
      RECT 0.000 74.064 0.024 74.088 ;
    END
  END wd_in[58]
  PIN wd_in[59]
    DIRECTION INPUT ;
    USE SIGNAL ;
    SHAPE ABUTMENT ;
    PORT
      LAYER M4 ;
      RECT 0.000 74.448 0.024 74.472 ;
    END
  END wd_in[59]
  PIN wd_in[60]
    DIRECTION INPUT ;
    USE SIGNAL ;
    SHAPE ABUTMENT ;
    PORT
      LAYER M4 ;
      RECT 0.000 74.832 0.024 74.856 ;
    END
  END wd_in[60]
  PIN wd_in[61]
    DIRECTION INPUT ;
    USE SIGNAL ;
    SHAPE ABUTMENT ;
    PORT
      LAYER M4 ;
      RECT 0.000 75.216 0.024 75.240 ;
    END
  END wd_in[61]
  PIN wd_in[62]
    DIRECTION INPUT ;
    USE SIGNAL ;
    SHAPE ABUTMENT ;
    PORT
      LAYER M4 ;
      RECT 0.000 75.600 0.024 75.624 ;
    END
  END wd_in[62]
  PIN wd_in[63]
    DIRECTION INPUT ;
    USE SIGNAL ;
    SHAPE ABUTMENT ;
    PORT
      LAYER M4 ;
      RECT 0.000 75.984 0.024 76.008 ;
    END
  END wd_in[63]
  PIN addr_in[0]
    DIRECTION INPUT ;
    USE SIGNAL ;
    SHAPE ABUTMENT ;
    PORT
      LAYER M4 ;
      RECT 0.000 77.664 0.024 77.688 ;
    END
  END addr_in[0]
  PIN addr_in[1]
    DIRECTION INPUT ;
    USE SIGNAL ;
    SHAPE ABUTMENT ;
    PORT
      LAYER M4 ;
      RECT 0.000 78.048 0.024 78.072 ;
    END
  END addr_in[1]
  PIN addr_in[2]
    DIRECTION INPUT ;
    USE SIGNAL ;
    SHAPE ABUTMENT ;
    PORT
      LAYER M4 ;
      RECT 0.000 78.432 0.024 78.456 ;
    END
  END addr_in[2]
  PIN addr_in[3]
    DIRECTION INPUT ;
    USE SIGNAL ;
    SHAPE ABUTMENT ;
    PORT
      LAYER M4 ;
      RECT 0.000 78.816 0.024 78.840 ;
    END
  END addr_in[3]
  PIN addr_in[4]
    DIRECTION INPUT ;
    USE SIGNAL ;
    SHAPE ABUTMENT ;
    PORT
      LAYER M4 ;
      RECT 0.000 79.200 0.024 79.224 ;
    END
  END addr_in[4]
  PIN addr_in[5]
    DIRECTION INPUT ;
    USE SIGNAL ;
    SHAPE ABUTMENT ;
    PORT
      LAYER M4 ;
      RECT 0.000 79.584 0.024 79.608 ;
    END
  END addr_in[5]
  PIN addr_in[6]
    DIRECTION INPUT ;
    USE SIGNAL ;
    SHAPE ABUTMENT ;
    PORT
      LAYER M4 ;
      RECT 0.000 79.968 0.024 79.992 ;
    END
  END addr_in[6]
  PIN addr_in[7]
    DIRECTION INPUT ;
    USE SIGNAL ;
    SHAPE ABUTMENT ;
    PORT
      LAYER M4 ;
      RECT 0.000 80.352 0.024 80.376 ;
    END
  END addr_in[7]
  PIN addr_in[8]
    DIRECTION INPUT ;
    USE SIGNAL ;
    SHAPE ABUTMENT ;
    PORT
      LAYER M4 ;
      RECT 0.000 80.736 0.024 80.760 ;
    END
  END addr_in[8]
  PIN addr_in[9]
    DIRECTION INPUT ;
    USE SIGNAL ;
    SHAPE ABUTMENT ;
    PORT
      LAYER M4 ;
      RECT 0.000 81.120 0.024 81.144 ;
    END
  END addr_in[9]
  PIN we_in
    DIRECTION INPUT ;
    USE SIGNAL ;
    SHAPE ABUTMENT ;
    PORT
      LAYER M4 ;
      RECT 0.000 82.800 0.024 82.824 ;
    END
  END we_in
  PIN ce_in
    DIRECTION INPUT ;
    USE SIGNAL ;
    SHAPE ABUTMENT ;
    PORT
      LAYER M4 ;
      RECT 0.000 83.184 0.024 83.208 ;
    END
  END ce_in
  PIN clk
    DIRECTION INPUT ;
    USE SIGNAL ;
    SHAPE ABUTMENT ;
    PORT
      LAYER M4 ;
      RECT 0.000 83.568 0.024 83.592 ;
    END
  END clk
  PIN VSS
    DIRECTION INOUT ;
    USE GROUND ;
    PORT
      LAYER M4 ;
      RECT 0.048 0.000 33.202 0.096 ;
      RECT 0.048 0.768 33.202 0.864 ;
      RECT 0.048 1.536 33.202 1.632 ;
      RECT 0.048 2.304 33.202 2.400 ;
      RECT 0.048 3.072 33.202 3.168 ;
      RECT 0.048 3.840 33.202 3.936 ;
      RECT 0.048 4.608 33.202 4.704 ;
      RECT 0.048 5.376 33.202 5.472 ;
      RECT 0.048 6.144 33.202 6.240 ;
      RECT 0.048 6.912 33.202 7.008 ;
      RECT 0.048 7.680 33.202 7.776 ;
      RECT 0.048 8.448 33.202 8.544 ;
      RECT 0.048 9.216 33.202 9.312 ;
      RECT 0.048 9.984 33.202 10.080 ;
      RECT 0.048 10.752 33.202 10.848 ;
      RECT 0.048 11.520 33.202 11.616 ;
      RECT 0.048 12.288 33.202 12.384 ;
      RECT 0.048 13.056 33.202 13.152 ;
      RECT 0.048 13.824 33.202 13.920 ;
      RECT 0.048 14.592 33.202 14.688 ;
      RECT 0.048 15.360 33.202 15.456 ;
      RECT 0.048 16.128 33.202 16.224 ;
      RECT 0.048 16.896 33.202 16.992 ;
      RECT 0.048 17.664 33.202 17.760 ;
      RECT 0.048 18.432 33.202 18.528 ;
      RECT 0.048 19.200 33.202 19.296 ;
      RECT 0.048 19.968 33.202 20.064 ;
      RECT 0.048 20.736 33.202 20.832 ;
      RECT 0.048 21.504 33.202 21.600 ;
      RECT 0.048 22.272 33.202 22.368 ;
      RECT 0.048 23.040 33.202 23.136 ;
      RECT 0.048 23.808 33.202 23.904 ;
      RECT 0.048 24.576 33.202 24.672 ;
      RECT 0.048 25.344 33.202 25.440 ;
      RECT 0.048 26.112 33.202 26.208 ;
      RECT 0.048 26.880 33.202 26.976 ;
      RECT 0.048 27.648 33.202 27.744 ;
      RECT 0.048 28.416 33.202 28.512 ;
      RECT 0.048 29.184 33.202 29.280 ;
      RECT 0.048 29.952 33.202 30.048 ;
      RECT 0.048 30.720 33.202 30.816 ;
      RECT 0.048 31.488 33.202 31.584 ;
      RECT 0.048 32.256 33.202 32.352 ;
      RECT 0.048 33.024 33.202 33.120 ;
      RECT 0.048 33.792 33.202 33.888 ;
      RECT 0.048 34.560 33.202 34.656 ;
      RECT 0.048 35.328 33.202 35.424 ;
      RECT 0.048 36.096 33.202 36.192 ;
      RECT 0.048 36.864 33.202 36.960 ;
      RECT 0.048 37.632 33.202 37.728 ;
      RECT 0.048 38.400 33.202 38.496 ;
      RECT 0.048 39.168 33.202 39.264 ;
      RECT 0.048 39.936 33.202 40.032 ;
      RECT 0.048 40.704 33.202 40.800 ;
      RECT 0.048 41.472 33.202 41.568 ;
      RECT 0.048 42.240 33.202 42.336 ;
      RECT 0.048 43.008 33.202 43.104 ;
      RECT 0.048 43.776 33.202 43.872 ;
      RECT 0.048 44.544 33.202 44.640 ;
      RECT 0.048 45.312 33.202 45.408 ;
      RECT 0.048 46.080 33.202 46.176 ;
      RECT 0.048 46.848 33.202 46.944 ;
      RECT 0.048 47.616 33.202 47.712 ;
      RECT 0.048 48.384 33.202 48.480 ;
      RECT 0.048 49.152 33.202 49.248 ;
      RECT 0.048 49.920 33.202 50.016 ;
      RECT 0.048 50.688 33.202 50.784 ;
      RECT 0.048 51.456 33.202 51.552 ;
      RECT 0.048 52.224 33.202 52.320 ;
      RECT 0.048 52.992 33.202 53.088 ;
      RECT 0.048 53.760 33.202 53.856 ;
      RECT 0.048 54.528 33.202 54.624 ;
      RECT 0.048 55.296 33.202 55.392 ;
      RECT 0.048 56.064 33.202 56.160 ;
      RECT 0.048 56.832 33.202 56.928 ;
      RECT 0.048 57.600 33.202 57.696 ;
      RECT 0.048 58.368 33.202 58.464 ;
      RECT 0.048 59.136 33.202 59.232 ;
      RECT 0.048 59.904 33.202 60.000 ;
      RECT 0.048 60.672 33.202 60.768 ;
      RECT 0.048 61.440 33.202 61.536 ;
      RECT 0.048 62.208 33.202 62.304 ;
      RECT 0.048 62.976 33.202 63.072 ;
      RECT 0.048 63.744 33.202 63.840 ;
      RECT 0.048 64.512 33.202 64.608 ;
      RECT 0.048 65.280 33.202 65.376 ;
      RECT 0.048 66.048 33.202 66.144 ;
      RECT 0.048 66.816 33.202 66.912 ;
      RECT 0.048 67.584 33.202 67.680 ;
      RECT 0.048 68.352 33.202 68.448 ;
      RECT 0.048 69.120 33.202 69.216 ;
      RECT 0.048 69.888 33.202 69.984 ;
      RECT 0.048 70.656 33.202 70.752 ;
      RECT 0.048 71.424 33.202 71.520 ;
      RECT 0.048 72.192 33.202 72.288 ;
      RECT 0.048 72.960 33.202 73.056 ;
      RECT 0.048 73.728 33.202 73.824 ;
      RECT 0.048 74.496 33.202 74.592 ;
      RECT 0.048 75.264 33.202 75.360 ;
      RECT 0.048 76.032 33.202 76.128 ;
      RECT 0.048 76.800 33.202 76.896 ;
      RECT 0.048 77.568 33.202 77.664 ;
      RECT 0.048 78.336 33.202 78.432 ;
      RECT 0.048 79.104 33.202 79.200 ;
      RECT 0.048 79.872 33.202 79.968 ;
      RECT 0.048 80.640 33.202 80.736 ;
      RECT 0.048 81.408 33.202 81.504 ;
      RECT 0.048 82.176 33.202 82.272 ;
      RECT 0.048 82.944 33.202 83.040 ;
      RECT 0.048 83.712 33.202 83.808 ;
    END
  END VSS
  PIN VDD
    DIRECTION INOUT ;
    USE POWER ;
    PORT
      LAYER M4 ;
      RECT 0.048 0.384 33.202 0.480 ;
      RECT 0.048 1.152 33.202 1.248 ;
      RECT 0.048 1.920 33.202 2.016 ;
      RECT 0.048 2.688 33.202 2.784 ;
      RECT 0.048 3.456 33.202 3.552 ;
      RECT 0.048 4.224 33.202 4.320 ;
      RECT 0.048 4.992 33.202 5.088 ;
      RECT 0.048 5.760 33.202 5.856 ;
      RECT 0.048 6.528 33.202 6.624 ;
      RECT 0.048 7.296 33.202 7.392 ;
      RECT 0.048 8.064 33.202 8.160 ;
      RECT 0.048 8.832 33.202 8.928 ;
      RECT 0.048 9.600 33.202 9.696 ;
      RECT 0.048 10.368 33.202 10.464 ;
      RECT 0.048 11.136 33.202 11.232 ;
      RECT 0.048 11.904 33.202 12.000 ;
      RECT 0.048 12.672 33.202 12.768 ;
      RECT 0.048 13.440 33.202 13.536 ;
      RECT 0.048 14.208 33.202 14.304 ;
      RECT 0.048 14.976 33.202 15.072 ;
      RECT 0.048 15.744 33.202 15.840 ;
      RECT 0.048 16.512 33.202 16.608 ;
      RECT 0.048 17.280 33.202 17.376 ;
      RECT 0.048 18.048 33.202 18.144 ;
      RECT 0.048 18.816 33.202 18.912 ;
      RECT 0.048 19.584 33.202 19.680 ;
      RECT 0.048 20.352 33.202 20.448 ;
      RECT 0.048 21.120 33.202 21.216 ;
      RECT 0.048 21.888 33.202 21.984 ;
      RECT 0.048 22.656 33.202 22.752 ;
      RECT 0.048 23.424 33.202 23.520 ;
      RECT 0.048 24.192 33.202 24.288 ;
      RECT 0.048 24.960 33.202 25.056 ;
      RECT 0.048 25.728 33.202 25.824 ;
      RECT 0.048 26.496 33.202 26.592 ;
      RECT 0.048 27.264 33.202 27.360 ;
      RECT 0.048 28.032 33.202 28.128 ;
      RECT 0.048 28.800 33.202 28.896 ;
      RECT 0.048 29.568 33.202 29.664 ;
      RECT 0.048 30.336 33.202 30.432 ;
      RECT 0.048 31.104 33.202 31.200 ;
      RECT 0.048 31.872 33.202 31.968 ;
      RECT 0.048 32.640 33.202 32.736 ;
      RECT 0.048 33.408 33.202 33.504 ;
      RECT 0.048 34.176 33.202 34.272 ;
      RECT 0.048 34.944 33.202 35.040 ;
      RECT 0.048 35.712 33.202 35.808 ;
      RECT 0.048 36.480 33.202 36.576 ;
      RECT 0.048 37.248 33.202 37.344 ;
      RECT 0.048 38.016 33.202 38.112 ;
      RECT 0.048 38.784 33.202 38.880 ;
      RECT 0.048 39.552 33.202 39.648 ;
      RECT 0.048 40.320 33.202 40.416 ;
      RECT 0.048 41.088 33.202 41.184 ;
      RECT 0.048 41.856 33.202 41.952 ;
      RECT 0.048 42.624 33.202 42.720 ;
      RECT 0.048 43.392 33.202 43.488 ;
      RECT 0.048 44.160 33.202 44.256 ;
      RECT 0.048 44.928 33.202 45.024 ;
      RECT 0.048 45.696 33.202 45.792 ;
      RECT 0.048 46.464 33.202 46.560 ;
      RECT 0.048 47.232 33.202 47.328 ;
      RECT 0.048 48.000 33.202 48.096 ;
      RECT 0.048 48.768 33.202 48.864 ;
      RECT 0.048 49.536 33.202 49.632 ;
      RECT 0.048 50.304 33.202 50.400 ;
      RECT 0.048 51.072 33.202 51.168 ;
      RECT 0.048 51.840 33.202 51.936 ;
      RECT 0.048 52.608 33.202 52.704 ;
      RECT 0.048 53.376 33.202 53.472 ;
      RECT 0.048 54.144 33.202 54.240 ;
      RECT 0.048 54.912 33.202 55.008 ;
      RECT 0.048 55.680 33.202 55.776 ;
      RECT 0.048 56.448 33.202 56.544 ;
      RECT 0.048 57.216 33.202 57.312 ;
      RECT 0.048 57.984 33.202 58.080 ;
      RECT 0.048 58.752 33.202 58.848 ;
      RECT 0.048 59.520 33.202 59.616 ;
      RECT 0.048 60.288 33.202 60.384 ;
      RECT 0.048 61.056 33.202 61.152 ;
      RECT 0.048 61.824 33.202 61.920 ;
      RECT 0.048 62.592 33.202 62.688 ;
      RECT 0.048 63.360 33.202 63.456 ;
      RECT 0.048 64.128 33.202 64.224 ;
      RECT 0.048 64.896 33.202 64.992 ;
      RECT 0.048 65.664 33.202 65.760 ;
      RECT 0.048 66.432 33.202 66.528 ;
      RECT 0.048 67.200 33.202 67.296 ;
      RECT 0.048 67.968 33.202 68.064 ;
      RECT 0.048 68.736 33.202 68.832 ;
      RECT 0.048 69.504 33.202 69.600 ;
      RECT 0.048 70.272 33.202 70.368 ;
      RECT 0.048 71.040 33.202 71.136 ;
      RECT 0.048 71.808 33.202 71.904 ;
      RECT 0.048 72.576 33.202 72.672 ;
      RECT 0.048 73.344 33.202 73.440 ;
      RECT 0.048 74.112 33.202 74.208 ;
      RECT 0.048 74.880 33.202 74.976 ;
      RECT 0.048 75.648 33.202 75.744 ;
      RECT 0.048 76.416 33.202 76.512 ;
      RECT 0.048 77.184 33.202 77.280 ;
      RECT 0.048 77.952 33.202 78.048 ;
      RECT 0.048 78.720 33.202 78.816 ;
      RECT 0.048 79.488 33.202 79.584 ;
      RECT 0.048 80.256 33.202 80.352 ;
      RECT 0.048 81.024 33.202 81.120 ;
      RECT 0.048 81.792 33.202 81.888 ;
      RECT 0.048 82.560 33.202 82.656 ;
      RECT 0.048 83.328 33.202 83.424 ;
    END
  END VDD
  OBS
    LAYER M1 ;
    RECT 0 0 33.250 84.000 ;
    LAYER M2 ;
    RECT 0 0 33.250 84.000 ;
    LAYER M3 ;
    RECT 0 0 33.250 84.000 ;
    LAYER M4 ;
    RECT 0 0 33.250 84.000 ;
  END
END fakeram7_sp_1024x64

END LIBRARY
